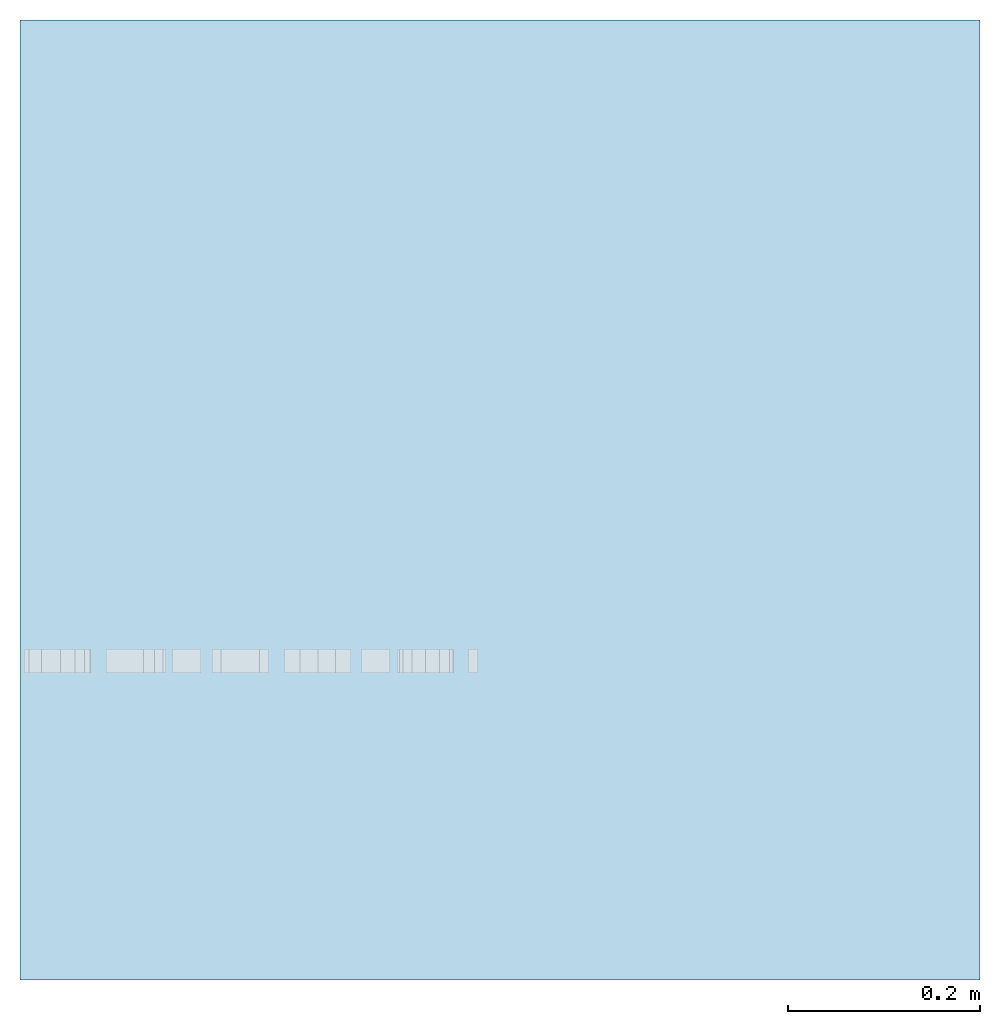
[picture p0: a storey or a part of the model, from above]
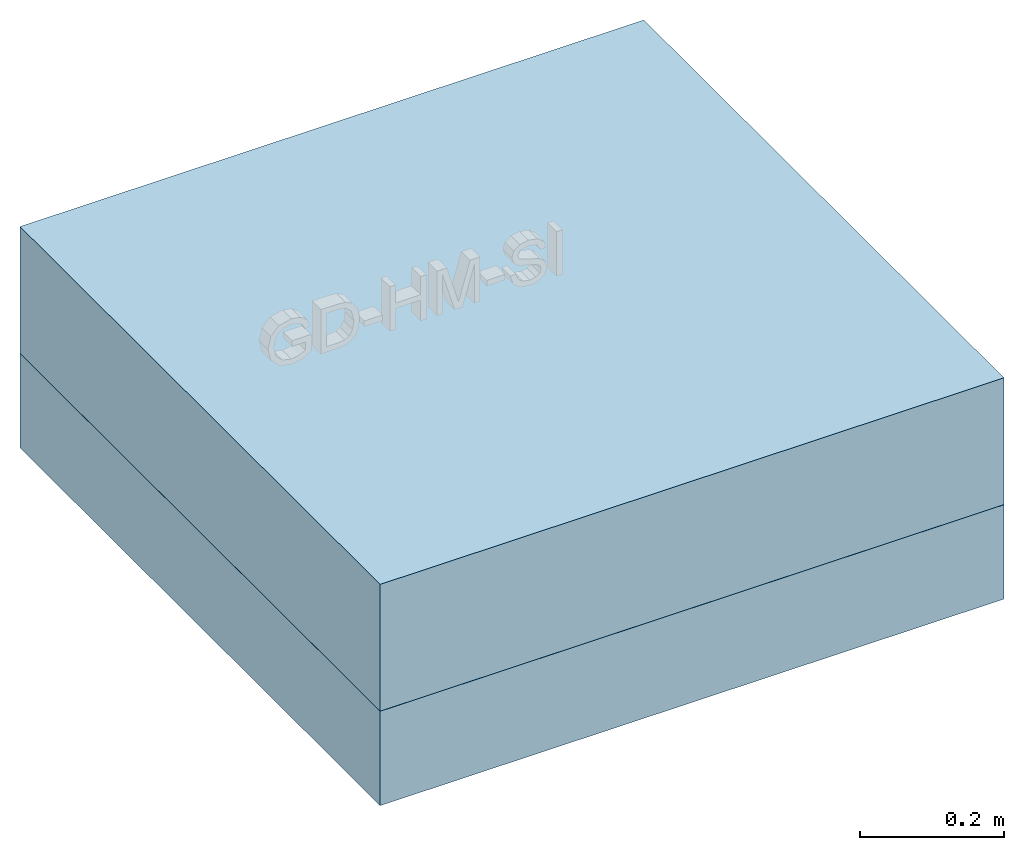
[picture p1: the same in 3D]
Properties of the parts of a building model (IFC4)

# File
Description: ViewDefinition [ReferenceView_V1.2], RevitIdentifiers [VersionGUID: 71a4b502-a2af-483b-88dc-542061cd4702, NumberOfSaves: 1], CoordinateReference [CoordinateBase: Gemeinsam genutzte Koordinaten], ExchangeRequirement [Architecture]
File name: 2018_01
Time: 2023-06-27T16:02:20+01:00
Written by: ODA SDAI 23.12
Made in: Autodesk Revit 24.0.5.432 (DEU) - IFC 24.0.5.432

# IfcProject, 2018_01
Phase: Projekt Status

# IfcSite, Default
RefLatitude: 48, 8, 15, 359802; RefLongitude: 11, 34, 47, 783432; RefElevation: 0 m
Pset_SiteCommon - Reference: Projektinformationen

# IfcBuildingElementProxy: Modelltext:075mm Arial, Modelltext:075mm Arial:2510258
In: Default
Type - Pset_BuildingElementProxyCommon - IsExternal: no
Pset_BuildingElementProxyCommon - Reference: 075mm Arial
Pset_EnvironmentalImpactIndicators - Reference: 075mm Arial
Qto_BuildingElementProxyQuantities - NetSurfaceArea: 0.0893112 m2; NetVolume: 0.000292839 m3

# IfcElementAssembly: Geschossdecken Baugruppe:fbimSg_Slab_bc_WOD_vis_at_NTR_natuREbuilt_GD-HM-SI_GK3_38cm, Geschossdecken Baugruppe:fbimSg_Slab_bc_WOD_vis_at_NTR_natuREbuilt_GD-HM-SI_GK3_38cm:2510273
In: Default
PredefinedType: USERDEFINED; Material: fbim_18108010_AT_015_Parkettboden, fbim_16051005_AT_225_Estrichbeton_E225, fbim_14104050_AT_035_MW-Trittschalldaemmplatte, fbim_10053020_AT_024_Splitt_2-4
Pset_ElementAssemblyCommon - Reference: fbimSg_Slab_bc_WOD_vis_at_NTR_natuREbuilt_GD-HM-SI_GK3_38cm; sets with these values: 2

# IfcSlab: Geschossdecke:fbimSg_Floor_sb_WOD_vis_at_NTR_natuREbuilt_MhS_GK3_o_21,5cm, Geschossdecke:fbimSg_Floor_sb_WOD_vis_at_NTR_natuREbuilt_MhS_GK3_o_21,5cm:2510261
In: Default
Type - PredefinedType: FLOOR; Material: fbim_18108010_AT_015_Parkettboden, fbim_16051005_AT_225_Estrichbeton_E225, fbim_14104050_AT_035_MW-Trittschalldaemmplatte, fbim_10053020_AT_024_Splitt_2-4
Type - Pset_SlabCommon - IsExternal: no
Pset_EnvironmentalImpactIndicators - Reference: fbimSg_Floor_sb_WOD_vis_at_NTR_natuREbuilt_MhS_GK3_o_21,5cm; sets with these values: 2
Pset_SlabCommon - Reference: fbimSg_Floor_sb_WOD_vis_at_NTR_natuREbuilt_MhS_GK3_o_21,5cm; PitchAngle: 0 deg; LoadBearing: no
Qto_SlabBaseQuantities - fbim_18108010_AT_015_Parkettboden, Width: 0.015 m; fbim_16051005_AT_225_Estrichbeton_E225, Width: 0.07 m; fbim_14104050_AT_035_MW-Trittschalldaemmplatte, Width: 0.03 m; fbim_10053020_AT_024_Splitt_2-4, Width: 0.1 m; Width: 0.215 m; Length: 1 m; Depth: 0.1 m; Perimeter: 4 m; GrossArea: 1 m2; GrossVolume: 0.1 m3; NetVolume: 0.215 m3

# IfcSlab: Geschossdecke:fbimSg_Slab_dp_INS_vis_at_NTR_natuREbuilt_MhS_GK3_k_16cm, Geschossdecke:fbimSg_Slab_dp_INS_vis_at_NTR_natuREbuilt_MhS_GK3_k_16cm:2510268
In: Default
Type - PredefinedType: FLOOR; Material: fbim_AT_KLH_Massivholz
Type - Pset_SlabCommon - IsExternal: no
Pset_EnvironmentalImpactIndicators - Reference: fbimSg_Slab_dp_INS_vis_at_NTR_natuREbuilt_MhS_GK3_k_16cm; sets with these values: 2
Pset_SlabCommon - PitchAngle: 0 deg; LoadBearing: no; Reference: fbimSg_Slab_dp_INS_vis_at_NTR_natuREbuilt_MhS_GK3_k_16cm
Qto_SlabBaseQuantities - Width: 1 m; Length: 1 m; Depth: 0.16 m; Perimeter: 4 m; GrossArea: 1 m2; GrossVolume: 0.16 m3; NetVolume: 0.16 m3
